! (c) 2009  Infineon Technologies AG, Munich
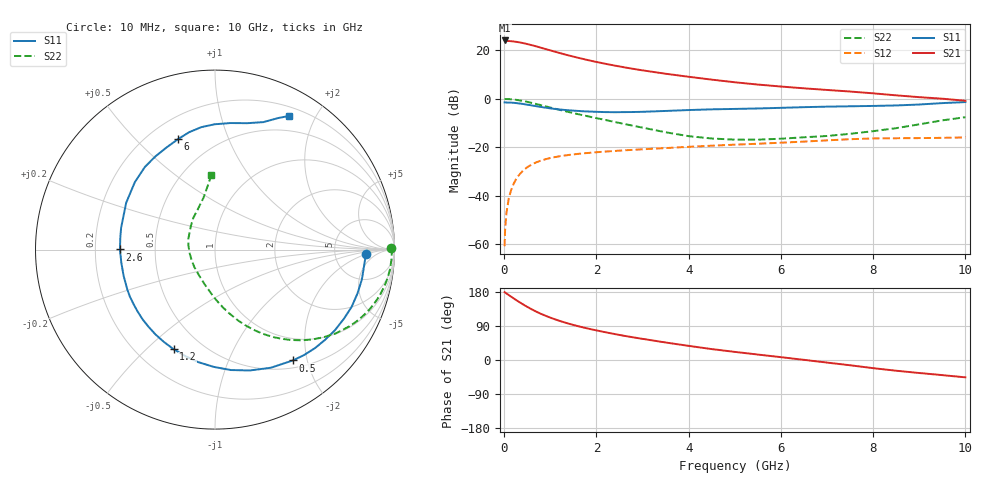
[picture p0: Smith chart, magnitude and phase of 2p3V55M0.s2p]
! Infineon Technologies  Discrete & RF Semiconductors
! BFP420
! VCE =  3.5 V,  IC =  5.0 mA
! Common Emitter S-Parameters:  Nov 2009
# GHz  S  MA  R  50
!  f  S11  S21  S12  S22
! GHz  MAG  ANG  MAG  ANG  MAG  ANG  MAG  ANG
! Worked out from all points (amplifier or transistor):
!   46 points, 10 MHz to 10 GHz, reference 50 ohm
!   highest |S21| = 24.1 dB at 10 MHz (marker M1)
!   |S21| within 3 dB of that: start of sweep to 796.7 MHz
!   unconditionally stable (mu >= 1): 3.026 GHz to end of sweep
!   at 300 MHz: K = 0.12, MSG = 27.7 dB, |S12| = -32.1 dB
!   at 1.7 GHz: K = 0.59, MSG = 19.5 dB, |S12| = -22.6 dB
!   at 10 GHz: K = 1.12, MAG = 5.4 dB, |S12| = -16.0 dB
!   lowest NFmin = 0.66 dB at 900 MHz
!   S11 on the Smith chart (normalised r, x): 10 MHz: 11, -2; 500 MHz: 0.61, -1.76; 1.2 GHz: 0.35, -0.61; 2.6 GHz: 0.31, +0.00; 6 GHz: 0.32, +0.67; 10 GHz: 0.30, +1.66
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0.01  0.8393 -1.5  16 179.0  0.0009 53.5  0.982 0.4
0.02  0.8395 -2.7  15.56 178.3  0.0019 71.2  0.9849 -1.2
0.1  0.8351 -11.5  15.57 171.4  0.0087 80.8  0.9814 -6.4
0.2  0.8253 -22.8  15.27 163.1  0.017 76.9  0.9638 -12.7
0.25  0.8147 -28.4  15.01 158.9  0.0211 74.3  0.9516 -15.8
0.35  0.7929 -39.4  14.51 151.2  0.0285 69.2  0.9202 -21.7
0.5  0.7547 -54.9  13.5 140.3  0.0384 62.2  0.8623 -29.7
0.6  0.7281 -64.7  12.78 133.6  0.0439 58.0  0.8203 -34.6
0.8  0.6768 -82.5  11.3 121.8  0.0528 50.9  0.7362 -42.9
1  0.6338 -98.5  9.981 111.9  0.0596 45.3  0.6584 -49.9
1.2  0.6008 -112.6  8.822 103.3  0.0648 40.9  0.5903 -55.9
1.4  0.5773 -125.1  7.842 95.9  0.069 37.5  0.5317 -61.1
1.7  0.552 -141.5  6.675 86.4  0.0741 33.5  0.4577 -67.8
2.2  0.5296 -164.3  5.261 73.1  0.0811 28.7  0.363 -77.5
2.6  0.5294 179.9  4.467 63.9  0.0858 25.7  0.302 -85.4
3.5  0.5594 152.2  3.286 46.2  0.0957 20.5  0.2029 -106.3
4.5  0.6039 130.3  2.482 28.8  0.1071 15.1  0.1509 -139.5
5.5  0.6296 115.5  1.964 14.4  0.1176 10.1  0.1428 -172.2
6  0.6487 108.6  1.787 7.5  0.1234 7.7  0.1493 171.9
7  0.6864 96.4  1.519 -6.8  0.138 1.7  0.1701 146.6
8.5  0.7268 75.7  1.175 -28.3  0.1528 -11.9  0.2468 112.4
10  0.8529 60.9  0.908 -45.8  0.1588 -20.8  0.4156 92.8
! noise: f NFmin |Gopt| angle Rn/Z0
0.9  0.66  0.21  31  0.15
1.8  1.05  0.09  93  0.13
2.4  1.14  0.14  119  0.13
3  1.24  0.17  165  0.11
4  1.41  0.31  -145  0.12
5  1.85  0.38  -119  0.21
6  2.3  0.45  -101  0.36
